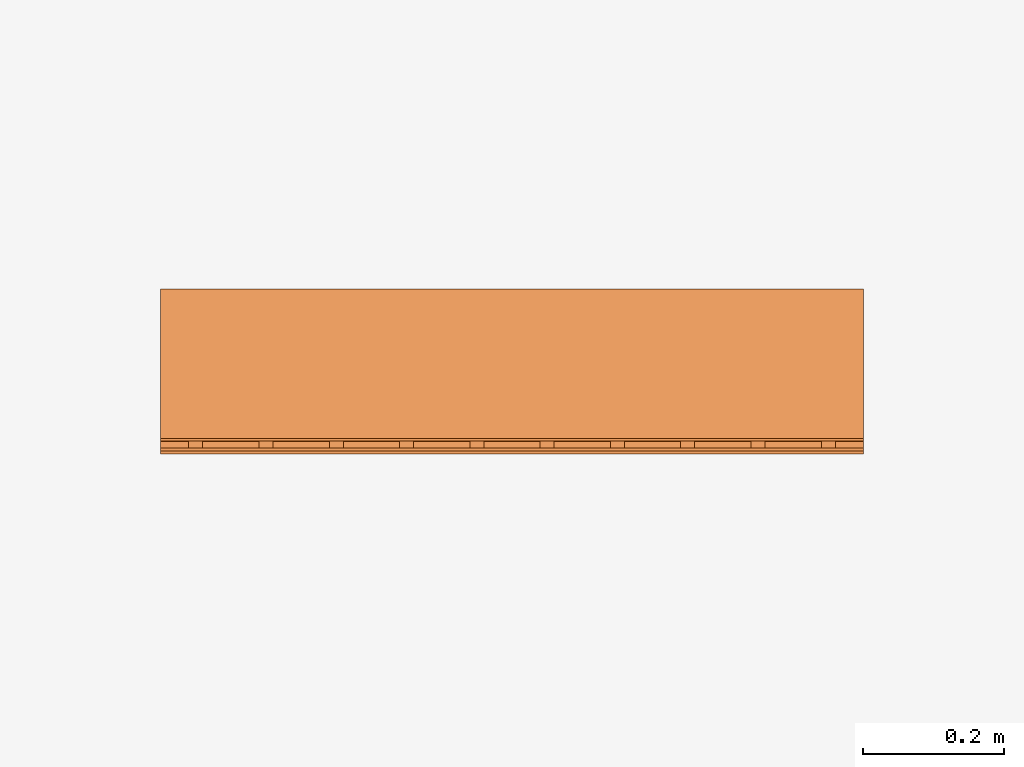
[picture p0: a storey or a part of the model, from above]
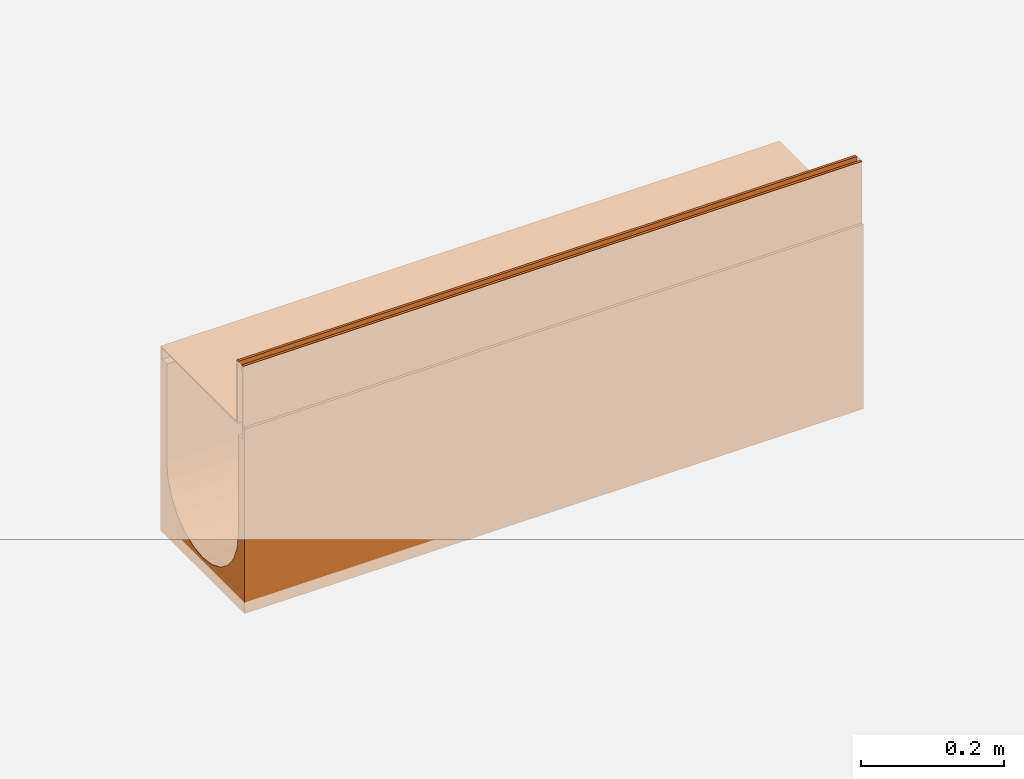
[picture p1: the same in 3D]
Properties of the parts of a building model (IFC2X3)

# File
Description: ViewDefinition [CoordinationView]
File name: 23211 - No 10.0 Constant Depth Channel - 1000mm LG - Invert Depth 290mm.ifc
Time: 2013-10-30T13:47:04
Written by: Autodesk Revit 2013
Made in: 20120221_2030(x64)

# IfcProject, Project Number
LongName: Project Name; Phase: Project Status

# IfcSite, Default
RefLatitude: 42, 21, 30, 344238; RefLongitude: -71, -3, -35, -194702; RefElevation: 0 mm

# IfcBuilding
Pset_BuildingCommon - NumberOfStoreys: 1
Other - Project Name: Project Name; Project Address: ## Street City, State Zip; Client Name: Owner; Project Issue Date: Issue Date; Project Status: Project Status; Project Number: Project Number

# IfcBuildingStorey, Level 1
LongName: Level 1; Elevation: 0 mm
Constraints - Elevation Base: 0; Elevation: 0 mm
Graphics - Color: 0; Symbol: M_Level Head - Circle: M_Level Head - Circle; Line Weight: 1; Line Pattern: Center; Symbol at End 2 Default: yes; Symbol at End 1 Default: no
Identity Data - Structural: no; Building Story: yes; Name: Level 1
Dimensions - Computation Height: 0 mm

# IfcBuildingElementProxy: 23211 - No 10.0 Constant Depth Channel - 1000mm LG - Invert Depth 290mm, Civil-Drainage-Channel-ACO-MultiDrain-M200D-Brickslot-Channel-System:23211 - No 10.0 Constant Depth Channel - 1000mm LG - Invert Depth 290mm:23211 - No 10.0 Constant Depth Channel - 1000mm LG - Invert Depth 290mm:196059
In: Level 1
Material: Steel, Galvanized, Vienite® Synthetic Resin Concrete
Dimensions - EndCap Position: 1000 mm; FloorCut_Length: -1000 mm; Brickslot Void Length: -1000 mm; Brickslot Access Void Depth: -6000 mm; Custom_Void_Length: 0 mm; Brickslot Access Unit Void Bottom Depth: -6105 mm; Brickslot Grating Void Depth: 0 mm; Length: 1000 mm; Volume: 20805290 mm3; Brickslot Access unit void length: -500 mm; FloorCut_Depth: 315 mm; Depth: 315 mm; EndCap_Height: 315 mm; FloorCut_HorPosition: 117.5 mm; InvDepth: 190 mm; FloorCut_Width: 235 mm; Length Drain: -1000 mm
Construction - 408997_Load Class C250 & D400_Brickslot_Access Unit_Galvanized Steel_500mm Long: no; 408995_Load Class C250 & D400_Brickslot Grating_Galvanized Steel_1000mm Long: yes; 23219 - Universal Endcap (Male End): no; 408996_Load Class C250 & D400_Brickslot Grating_Galvanized Steel_500mm Long: no; 23219 - Universal Endcap (Female End): no; Constant Depth Channel_1000: yes; 23410_Sump Unit: no; Shallow Depth Channel with seal: no; Shallow Depth Channel: no; Constant Depth Channel_500: no
Constraints - Moves With Nearby Elements: no; Level: Level: Level 1
Phasing - Phase Created: New Construction
Pset_BuildingElementProxyCommon - Reference: 23211 - No 10.0 Constant Depth Channel - 1000mm LG - Invert Depth 290mm
Data - Hydraulic Performance: http://www.aco.co.uk/download.php?id=173; Concrete Surround Volume - Load Class B 125 - C 250 - Concrete Pavement: 0.19m³/m; Channel C.S.A: 0.043m²; Concrete Surround Volume - Load Class A 15 - Concrete Pavement: 0.12m³/m; Invert Depth: 290mm; Product Standard: BS EN 1433:2002, CE marked; Product Dimensions: 1000mm x 235mm x 315mm (LxWxH); Pre-formed Outlet Ø: N/A; Concrete Surround Volume - Load Class D 400 - Concrete Pavement: 0.26m³/m; Load Class: A 15 - D 400; Product Weight: 34.2 Kg; Installation - Concrete Grade: Refer to brochure; ACO Hydraulic Design Software: http://www.acodesign.co.uk
Green Building Properties - Channel Recyclable: Fully recyclable; Edge Rail Recycled Material Content: Between 40% - 90%; Edge Rail Recyclable: Fully recyclable; Channel Recycled Material Content: 20% minimum
Identity Data - Telephone: +44 (0)1462 816666; OmniClass Number: 23.70.50.24; Assembly Code: D2040; Type Comments: ACO MultiDrain M200D 10.0 Constant Depth Channel 1000mm Long; Watermark 2: This file is water marked and users are prohibited to reproduce, adapt, distribute this information; Cost: 0; Model: ACO MultiDrain MD Brickslot - M200D; OmniClass Title: Rainwater Removal; Fax: +44 (0)1462 815895; Address: ACO Business Park, Hitchin Road, Shefford, Bedfordshire, United Kingdom SG17 5TE; Watermarked By: www.aco.co.uk; Assembly Description: Rain Water Drainage; Model Description: Channel drainage system; URL: www.aco.co.uk; Watermarked With: BIM Manager Premium Suite; e-mail Technical: technical@aco.co.uk; Manufacturer: ACO Technologies plc - ACO Water Management Division; Watermark 1: This file is the property of ACO Technologies PLC; Product Page URL: http://www.aco.co.uk/product_detail.php?id=58; Price: POA - contact ACO; Product brochure: http://www.aco.co.uk/download.php?id=173; Product Code: 23211; e-mail Sales: customersupport@aco.co.uk; Maintenance guidelines: http://www.aco.co.uk/download.php?id=173; Installation guidelines: http://www.aco.co.uk/download.php?id=173
Materials and Finishes - Channel Material: Vienite® Synthetic Resin Concrete; Edge Rail Material: Steel; Edge Rail Colour: Silver; Channel Colour: Brown; Edge Rail Finish: Pre-galvanised
General - TagNumber: 0; SerialNumber: 0
Other - CreatedBy: www.aco.co.uk; Revision: 1
Model Properties - Brickslot Access Unit Product code 408997: Load Class C250/D400 - Brickslot Access Unit Galvanised Steel - 500mm long x 105mm high - 10mm Slot - Intake area - 10000mm²/m 8.5 Kg; Brickslot Grating Product code 408995: Load Class C250/D400 - Brickslot Galvanized Steel - 1000mm long x 105mm high - 10mm Slot - Intake area - 10000mm²/m - 9.8kg; End Cap Product code 23219: No. 306 Universal End Cap - 235mm wide x 365mm long - Spigot Ø160mm x 75mm long - Silver - Polypropylene - 0.4kg; Brickslot Grating Product code 408996: Load Class C250/D400 - Brickslot Galvanized Steel - 500mm long x 105mm high - 10mm Slot - Intake area - 10000mm²/m - 4.8kg

# IfcOpeningElement: Opening (2)
In: Level 1
Constraints - Related to Mass: no; Height Offset From Level: 0 mm; Room Bounding: yes; Level: Level: Level 1
Structural - Enable Analytical Model: no; Structural: no
Dimensions - Area: 24982000 mm2; Perimeter: 20000 mm; Volume: 9928785000 mm3; Thickness: 400 mm
Phasing - Phase Created: New Construction
Construction - Default Thickness: 400 mm; Function: 0
Analytical Properties - Roughness: 1; Thermal mass: 543920; Absorptance: 0.1; Heat Transfer Coefficient (U): 2.0925; Thermal Resistance (R): 0.477897
Graphics - Coarse Scale Fill Color: 0
Materials and Finishes - Structural Material: Earth

# IfcSlab: Floor:Generic Floor - 400mm, Floor:Generic Floor - 400mm:193825
In: Level 1
PredefinedType: FLOOR; Material: Earth 400 mm
Constraints - Related to Mass: no; Height Offset From Level: 0 mm; Room Bounding: yes; Level: Level: Level 1
Structural - Enable Analytical Model: no; Structural: no
Dimensions - Area: 24982000 mm2; Perimeter: 20000 mm; Volume: 9928785000 mm3; Thickness: 400 mm
Phasing - Phase Created: New Construction
Pset_SlabCommon - Reference: Generic Floor - 400mm; IsExternal: no; LoadBearing: yes
Construction - Default Thickness: 400 mm; Function: 0
Analytical Properties - Roughness: 1; Thermal mass: 543920; Absorptance: 0.1; Heat Transfer Coefficient (U): 2.0925; Thermal Resistance (R): 0.477897
Graphics - Coarse Scale Fill Color: 0
Materials and Finishes - Structural Material: Earth
